One B-rep face of a CAD part: STEP entity #29.
In plain terms, the planar face has unit normal (1, 0, 0).
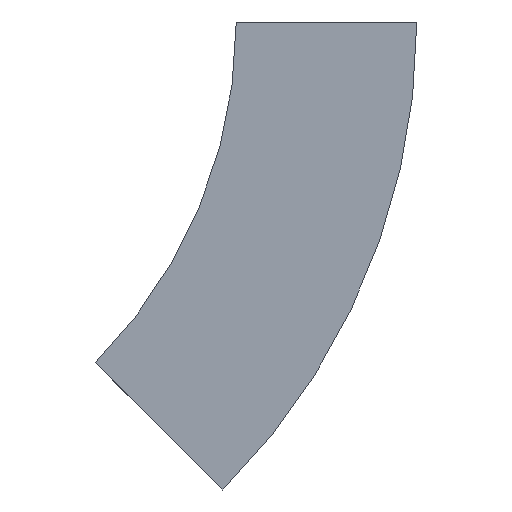
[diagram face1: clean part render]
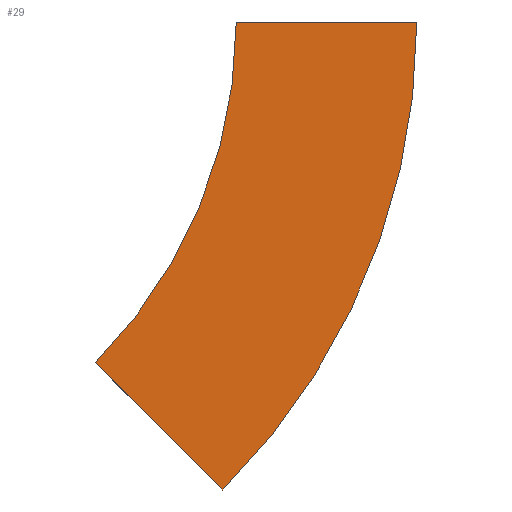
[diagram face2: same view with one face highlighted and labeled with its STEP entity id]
Its self-contained STEP definition (entity closure, numbers rounded to 3 decimals):
#12 = CARTESIAN_POINT ( 'NONE',  ( 0., -112.5, 0. ) ) ;
#29 = ADVANCED_FACE ( 'NONE', ( #328 ), #490, .F. ) ;
#49 = CARTESIAN_POINT ( 'NONE',  ( 0., -112.5, 0. ) ) ;
#52 = ORIENTED_EDGE ( 'NONE', *, *, #409, .F. ) ;
#69 = DIRECTION ( 'NONE',  ( 0., -1., 0. ) ) ;
#85 = ORIENTED_EDGE ( 'NONE', *, *, #398, .T. ) ;
#89 = EDGE_LOOP ( 'NONE', ( #52, #242, #368, #85 ) ) ;
#95 = CARTESIAN_POINT ( 'NONE',  ( 0., 0., 0. ) ) ;
#101 = CARTESIAN_POINT ( 'NONE',  ( 0., 87.868, -212.132 ) ) ;
#111 = CARTESIAN_POINT ( 'NONE',  ( 0., -112.5, 0. ) ) ;
#129 = AXIS2_PLACEMENT_3D ( 'NONE', #111, #293, #542 ) ;
#150 = DIRECTION ( 'NONE',  ( 0., 1., 0. ) ) ;
#154 = CARTESIAN_POINT ( 'NONE',  ( 0., 8.318, -291.682 ) ) ;
#172 = VECTOR ( 'NONE', #150, 1000. ) ;
#212 = VERTEX_POINT ( 'NONE', #267 ) ;
#230 = DIRECTION ( 'NONE',  ( 1., 0., 0. ) ) ;
#234 = DIRECTION ( 'NONE',  ( 0., -1., 0. ) ) ;
#242 = ORIENTED_EDGE ( 'NONE', *, *, #453, .F. ) ;
#267 = CARTESIAN_POINT ( 'NONE',  ( 0., 8.318, -291.682 ) ) ;
#278 = AXIS2_PLACEMENT_3D ( 'NONE', #503, #230, #69 ) ;
#282 = LINE ( 'NONE', #154, #397 ) ;
#293 = DIRECTION ( 'NONE',  ( -1., 0., 0. ) ) ;
#328 = FACE_OUTER_BOUND ( 'NONE', #89, .T. ) ;
#335 = VERTEX_POINT ( 'NONE', #95 ) ;
#341 = AXIS2_PLACEMENT_3D ( 'NONE', #549, #414, #234 ) ;
#349 = VERTEX_POINT ( 'NONE', #49 ) ;
#365 = VERTEX_POINT ( 'NONE', #101 ) ;
#368 = ORIENTED_EDGE ( 'NONE', *, *, #408, .T. ) ;
#397 = VECTOR ( 'NONE', #499, 1000. ) ;
#398 = EDGE_CURVE ( 'NONE', #212, #365, #282, .T. ) ;
#408 = EDGE_CURVE ( 'NONE', #349, #212, #449, .T. ) ;
#409 = EDGE_CURVE ( 'NONE', #335, #365, #470, .T. ) ;
#414 = DIRECTION ( 'NONE',  ( 1., 0., 0. ) ) ;
#449 = CIRCLE ( 'NONE', #278, 412.5 ) ;
#453 = EDGE_CURVE ( 'NONE', #349, #335, #496, .T. ) ;
#470 = CIRCLE ( 'NONE', #341, 300. ) ;
#490 = PLANE ( 'NONE',  #129 ) ;
#496 = LINE ( 'NONE', #12, #172 ) ;
#499 = DIRECTION ( 'NONE',  ( 0., 0.707, 0.707 ) ) ;
#503 = CARTESIAN_POINT ( 'NONE',  ( 0., 300., 0. ) ) ;
#542 = DIRECTION ( 'NONE',  ( 0., 0., 1. ) ) ;
#549 = CARTESIAN_POINT ( 'NONE',  ( 0., 300., 0. ) ) ;
